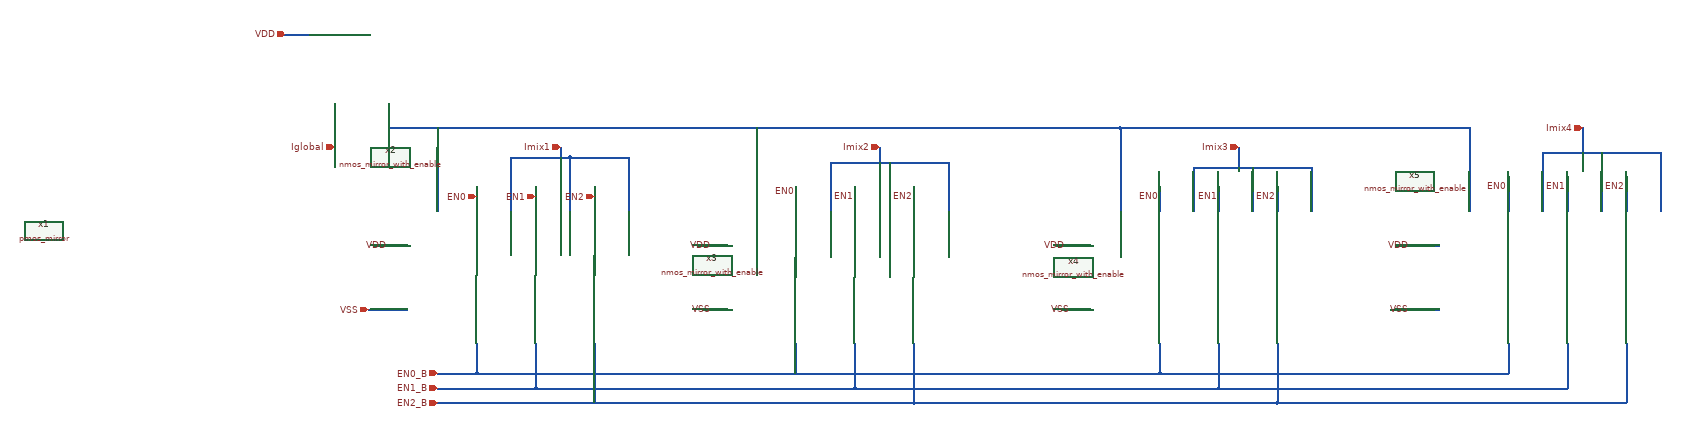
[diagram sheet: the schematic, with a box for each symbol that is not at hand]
v {xschem version=3.4.8RC file_version=1.3}
G {}
K {}
V {}
S {}
F {}
E {}
N 270 -960 670 -960 {lab=#net1}
N 670 -960 1070 -960 {lab=#net1}
N 1070 -960 1080 -960 {lab=#net1}
N 1460 -960 1470 -960 {lab=#net1}
N 1080 -960 1460 -960 {lab=#net1}
N 60 -1150 110 -1150 {lab=VDD}
N 160 -1010 160 -920 {lab=Iglobal}
N 370 -950 370 -790 {lab=#net1}
N 370 -960 370 -950 {lab=#net1}
N 1020 -960 1020 -790 {lab=#net1}
N 1760 -950 1760 -790 {lab=#net1}
N 1760 -960 1760 -950 {lab=#net1}
N 1470 -960 1760 -960 {lab=#net1}
N 270 -1010 270 -960 {lab=#net1}
N 450 -840 450 -790 {lab=EN0}
N 570 -840 570 -790 {lab=EN1}
N 690 -840 690 -790 {lab=EN2}
N 690 -520 690 -480 {lab=EN2_B}
N 570 -520 570 -480 {lab=EN1_B}
N 450 -520 450 -480 {lab=EN0_B}
N 1100 -840 1100 -790 {lab=EN0}
N 1220 -840 1220 -790 {lab=EN1}
N 1340 -840 1340 -790 {lab=EN2}
N 1340 -520 1340 -480 {lab=EN2_B}
N 1220 -520 1220 -480 {lab=EN1_B}
N 1100 -520 1100 -480 {lab=EN0_B}
N 520 -830 520 -790 {lab=Imix1}
N 640 -830 640 -790 {lab=Imix1}
N 760 -840 760 -790 {lab=Imix1}
N 450 -480 450 -460 {lab=EN0_B}
N 450 -460 1840 -460 {lab=EN0_B}
N 1840 -520 1840 -460 {lab=EN0_B}
N 1100 -480 1100 -460 {lab=EN0_B}
N 570 -480 570 -430 {lab=EN1_B}
N 1220 -480 1220 -430 {lab=EN1_B}
N 570 -430 1220 -430 {lab=EN1_B}
N 1220 -430 1950 -430 {lab=EN1_B}
N 1960 -520 1960 -430 {lab=EN1_B}
N 1950 -430 1960 -430 {lab=EN1_B}
N 690 -480 690 -400 {lab=EN2_B}
N 700 -400 1340 -400 {lab=EN2_B}
N 1340 -480 1340 -400 {lab=EN2_B}
N 1340 -400 2080 -400 {lab=EN2_B}
N 2080 -520 2080 -400 {lab=EN2_B}
N 370 -460 450 -460 {lab=EN0_B}
N 370 -430 570 -430 {lab=EN1_B}
N 370 -400 700 -400 {lab=EN2_B}
N 1840 -460 2550 -460 {lab=EN0_B}
N 2550 -520 2550 -460 {lab=EN0_B}
N 1960 -430 2670 -430 {lab=EN1_B}
N 2670 -520 2670 -430 {lab=EN1_B}
N 2080 -400 2790 -400 {lab=EN2_B}
N 2790 -520 2790 -400 {lab=EN2_B}
N 240 -720 310 -720 {lab=#net2}
N 230 -590 310 -590 {lab=VSS}
N 900 -720 960 -720 {lab=VDD}
N 910 -590 960 -590 {lab=VSS}
N 1630 -720 1700 -720 {lab=VDD}
N 1640 -590 1700 -590 {lab=VSS}
N 2320 -720 2400 -720 {lab=VDD}
N 2400 -720 2410 -720 {lab=VDD}
N 2310 -590 2410 -590 {lab=VSS}
N 1760 -960 2460 -960 {lab=#net1}
N 2470 -960 2470 -790 {lab=#net1}
N 2460 -960 2470 -960 {lab=#net1}
N 1840 -840 1840 -790 {lab=EN0}
N 1960 -840 1960 -790 {lab=EN1}
N 2080 -840 2080 -790 {lab=EN2}
N 2550 -860 2550 -790 {lab=EN0}
N 2670 -860 2670 -790 {lab=EN1}
N 2790 -860 2790 -790 {lab=EN2}
N 520 -860 520 -830 {lab=Imix1}
N 640 -860 640 -830 {lab=Imix1}
N 760 -860 760 -840 {lab=Imix1}
N 1170 -870 1170 -790 {lab=Imix2}
N 1290 -870 1290 -790 {lab=Imix2}
N 1410 -870 1410 -790 {lab=Imix2}
N 1910 -870 1910 -790 {lab=Imix3}
N 2030 -870 2030 -790 {lab=Imix3}
N 2150 -870 2150 -790 {lab=Imix3}
N 2620 -910 2620 -790 {lab=Imix4}
N 2740 -910 2740 -790 {lab=Imix4}
N 2860 -910 2860 -790 {lab=Imix4}
N 520 -900 520 -860 {lab=Imix1}
N 520 -900 640 -900 {lab=Imix1}
N 640 -900 640 -860 {lab=Imix1}
N 640 -900 760 -900 {lab=Imix1}
N 760 -900 760 -860 {lab=Imix1}
N 620 -920 620 -900 {lab=Imix1}
N 1170 -890 1170 -870 {lab=Imix2}
N 1170 -890 1410 -890 {lab=Imix2}
N 1410 -890 1410 -870 {lab=Imix2}
N 1290 -890 1290 -870 {lab=Imix2}
N 1270 -920 1270 -890 {lab=Imix2}
N 1910 -880 1910 -870 {lab=Imix3}
N 1910 -880 2150 -880 {lab=Imix3}
N 2150 -880 2150 -870 {lab=Imix3}
N 2030 -880 2030 -870 {lab=Imix3}
N 2000 -920 2000 -880 {lab=Imix3}
N 2620 -910 2860 -910 {lab=Imix4}
N 2700 -960 2700 -910 {lab=Imix4}
C {/foss/designs/NYCMOS/designs/mirrors/schematic/pmos_mirror.sym} -430 -750 0 0 {name=x1}
C {title.sym} 190 -60 0 0 {name=l1 author="Charbel El Haddad"}
C {iopin.sym} 60 -1150 2 0 {name=p2 lab=VDD}
C {iopin.sym} 160 -920 0 0 {name=p3 lab=Iglobal}
C {/foss/designs/NYCMOS/designs/mirrors/schematic/nmos_mirror_with_enable.sym} 70 -610 0 0 {name=x2}
C {/foss/designs/NYCMOS/designs/mirrors/schematic/nmos_mirror_with_enable.sym} 720 -610 0 0 {name=x3}
C {/foss/designs/NYCMOS/designs/mirrors/schematic/nmos_mirror_with_enable.sym} 1460 -610 0 0 {name=x4}
C {iopin.sym} 370 -460 2 0 {name=p1 lab=EN0_B}
C {iopin.sym} 370 -430 2 0 {name=p4 lab=EN1_B}
C {iopin.sym} 370 -400 2 0 {name=p5 lab=EN2_B}
C {/foss/designs/NYCMOS/designs/mirrors/schematic/nmos_mirror_with_enable.sym} 2170 -610 0 0 {name=x5}
C {iopin.sym} 230 -590 2 0 {name=p7 lab=VSS}
C {lab_wire.sym} 930 -720 0 0 {name=p8 sig_type=std_logic lab=VDD}
C {lab_wire.sym} 1650 -720 0 0 {name=p9 sig_type=std_logic lab=VDD}
C {lab_wire.sym} 2350 -720 0 0 {name=p10 sig_type=std_logic lab=VDD}
C {lab_wire.sym} 930 -590 0 0 {name=p11 sig_type=std_logic lab=VSS}
C {lab_wire.sym} 1660 -590 0 0 {name=p12 sig_type=std_logic lab=VSS}
C {lab_wire.sym} 2350 -590 0 0 {name=p13 sig_type=std_logic lab=VSS}
C {iopin.sym} 450 -820 0 0 {name=p14 lab=EN0}
C {iopin.sym} 570 -820 0 0 {name=p15 lab=EN1}
C {iopin.sym} 690 -820 0 0 {name=p16 lab=EN2}
C {lab_wire.sym} 1100 -830 0 0 {name=p17 sig_type=std_logic lab=EN0}
C {lab_wire.sym} 1840 -820 0 0 {name=p18 sig_type=std_logic lab=EN0}
C {lab_wire.sym} 2550 -840 0 0 {name=p19 sig_type=std_logic lab=EN0}
C {lab_wire.sym} 1220 -820 0 0 {name=p20 sig_type=std_logic lab=EN1}
C {lab_wire.sym} 1960 -820 0 0 {name=p21 sig_type=std_logic lab=EN1}
C {lab_wire.sym} 2670 -840 0 0 {name=p22 sig_type=std_logic lab=EN1}
C {lab_wire.sym} 1340 -820 0 0 {name=p23 sig_type=std_logic lab=EN2}
C {lab_wire.sym} 2080 -820 0 0 {name=p24 sig_type=std_logic lab=EN2}
C {lab_wire.sym} 2790 -840 0 0 {name=p25 sig_type=std_logic lab=EN2}
C {iopin.sym} 620 -920 0 0 {name=p26 lab=Imix1}
C {iopin.sym} 1270 -920 0 0 {name=p27 lab=Imix2}
C {iopin.sym} 2000 -920 0 0 {name=p28 lab=Imix3}
C {iopin.sym} 2700 -960 0 0 {name=p29 lab=Imix4}
C {lab_wire.sym} 270 -720 0 0 {name=p6 sig_type=std_logic lab=VDD}
